# LEF file generated by Abstract Generator version 5.5.12 on Aug 29 11:42:45 2003
#
# Contains LEF for all bins.
# Options:   [ ] Antenna
#            [ ] Geometry
#            [x] Technology

VERSION 5.3 ;
NAMESCASESENSITIVE ON ;
BUSBITCHARS "[]" ;
DIVIDERCHAR "/" ;


UNITS
  DATABASE MICRONS 1000 ;
END UNITS
MANUFACTURINGGRID 0.001 ;
LAYER diffusion
  TYPE	MASTERSLICE ;
END diffusion

LAYER poly
  TYPE	MASTERSLICE ;
END poly

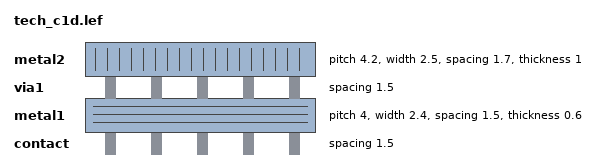
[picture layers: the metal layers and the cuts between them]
LAYER contact
  TYPE	CUT ;
  SPACING	1.5 ;
END contact

LAYER metal1
  TYPE		ROUTING ;
  DIRECTION	HORIZONTAL ;
  PITCH		4.0  ;
  OFFSET	0  ;
  WIDTH		2.4 ;
  SPACING	1.5 ;
  RESISTANCE	RPERSQ 0.05 ;
  CAPACITANCE	CPERSQDIST 0.000027 ;
  EDGECAPACITANCE 1.000000e-04 ;
  HEIGHT 1 ;
  THICKNESS 0.6 ;
  WIREEXTENSION 0 ;
END metal1

LAYER via1
  TYPE	CUT ;
  SPACING	1.5 ;
END via1

LAYER metal2
  TYPE		ROUTING ;
  DIRECTION	VERTICAL ;
  PITCH		4.2  ;
  OFFSET	0  ;
  WIDTH		2.5 ;
  SPACING	1.7 ;
  RESISTANCE	RPERSQ 0.03 ;
  CAPACITANCE	CPERSQDIST 0.0000156 ;
  EDGECAPACITANCE 1.000000e-04 ;
  HEIGHT 1 ;
  THICKNESS 1 ;
  WIREEXTENSION 0 ;
END metal2



SPACING
  SAMENET poly  diffusion	0.500 ;
  SAMENET contact  diffusion	1.000 ;
  SAMENET via1  contact	1.500 ;
  SAMENET metal1  contact	0.500 ;
  SAMENET poly  contact	0.700 ;
  SAMENET diffusion  contact	1.000 ;
  SAMENET metal2  via1	0.500 ;
  SAMENET metal1  via1	0.500 ;
 
END SPACING

VIA VIA12 DEFAULT
  LAYER metal1 ;
    RECT -1.25 -1.25 1.25 1.25 ;
  LAYER via1 ;
    RECT -0.75 -0.75 0.75 0.75 ;
  LAYER metal2 ;
    RECT -1.25 -1.25 1.25 1.25 ;
  RESISTANCE 1.700000e-01 ;
END VIA12 



VIARULE viaSP21 GENERATE
  LAYER metal1 ;
    DIRECTION HORIZONTAL ;
    WIDTH 2.4 TO 25 ;
    OVERHANG 0.5 ;
    METALOVERHANG 0.5 ;
  LAYER metal2 ;
    DIRECTION VERTICAL ;
    WIDTH 2.5 TO 25 ;
    OVERHANG 0.5 ;
    METALOVERHANG 0.5 ;
  LAYER via1 ;
    RECT -0.75 -0.75 0.75 0.75 ;
    SPACING 3.0 BY 3.0 ;
END viaSP21



SITE  corner
    CLASS	PAD ;
    SYMMETRY	R90 Y ;
    SIZE	304.900 BY 304.900 ;
END  corner

SITE  CORE
    CLASS	CORE ;
    SYMMETRY	Y ;
    SIZE	0.01 BY 48.700 ;
END  CORE

SITE  IO
    CLASS	PAD ;
    SYMMETRY	Y R90 ;
    SIZE	0.1 BY 304.900 ;
END  IO


END LIBRARY
